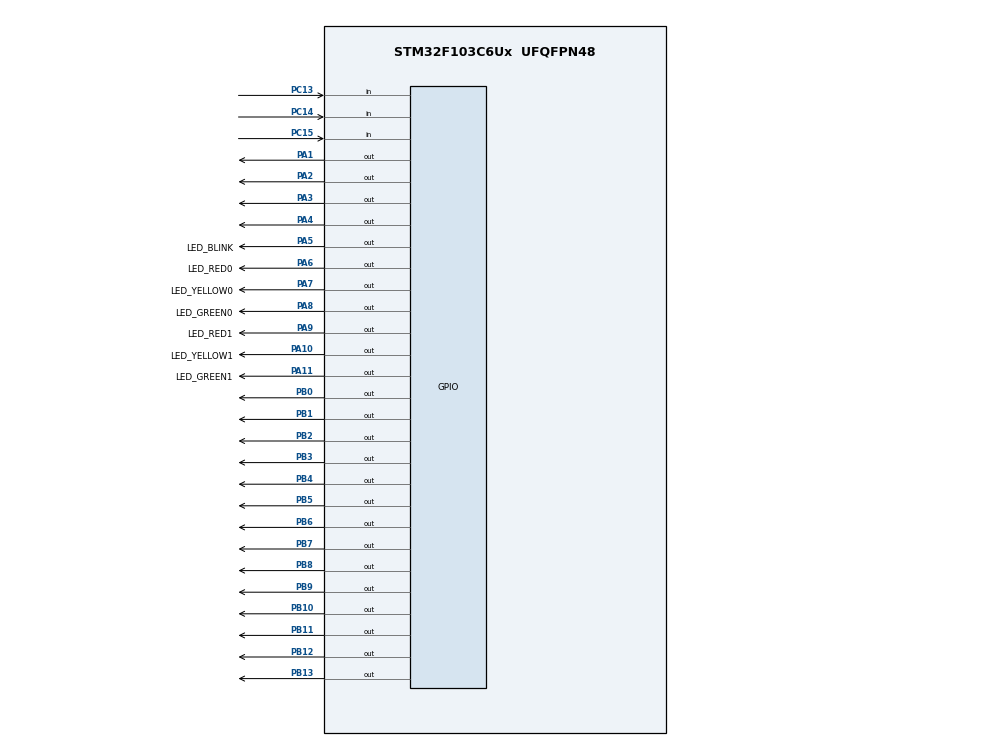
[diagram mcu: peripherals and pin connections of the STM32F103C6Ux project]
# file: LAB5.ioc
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Mcu.Family=STM32F1
Mcu.Name=STM32F103C6Ux
Mcu.Package=UFQFPN48
NVIC.PriorityGroup=NVIC_PRIORITYGROUP_4
NVIC.TIM2_IRQn=true\:0\:0\:false\:false\:true\:true\:true
PA1.Signal=GPIO_Output
PA10.GPIO_Label=LED_YELLOW1
PA10.Signal=GPIO_Output
PA11.GPIO_Label=LED_GREEN1
PA11.Signal=GPIO_Output
PA2.Signal=GPIO_Output
PA3.Signal=GPIO_Output
PA4.Signal=GPIO_Output
PA5.GPIO_Label=LED_BLINK
PA5.Signal=GPIO_Output
PA6.GPIO_Label=LED_RED0
PA6.Signal=GPIO_Output
PA7.GPIO_Label=LED_YELLOW0
PA7.Signal=GPIO_Output
PA8.GPIO_Label=LED_GREEN0
PA8.Signal=GPIO_Output
PA9.GPIO_Label=LED_RED1
PA9.Signal=GPIO_Output
PB0.Signal=GPIO_Output
PB1.Signal=GPIO_Output
PB10.Signal=GPIO_Output
PB11.Signal=GPIO_Output
PB12.Signal=GPIO_Output
PB13.Signal=GPIO_Output
PB2.Signal=GPIO_Output
PB3.Signal=GPIO_Output
PB4.Signal=GPIO_Output
PB5.Signal=GPIO_Output
PB6.Signal=GPIO_Output
PB7.Signal=GPIO_Output
PB8.Signal=GPIO_Output
PB9.Signal=GPIO_Output
PC13-TAMPER-RTC.GPIO_PuPd=GPIO_PULLUP
PC13-TAMPER-RTC.Signal=GPIO_Input
PC14-OSC32_IN.GPIO_PuPd=GPIO_PULLUP
PC14-OSC32_IN.Signal=GPIO_Input
PC15-OSC32_OUT.GPIO_PuPd=GPIO_PULLUP
PC15-OSC32_OUT.Signal=GPIO_Input
ProjectManager.HeapSize=0x200
ProjectManager.StackSize=0x400
ProjectManager.TargetToolchain=STM32CubeIDE
RCC.APB1Freq_Value=8000000
RCC.APB2Freq_Value=8000000
TIM2.Period=9
TIM2.Prescaler=7999
VP_SYS_VS_ND.Mode=No_Debug
VP_TIM2_VS_ClockSourceINT.Mode=Internal
board=custom

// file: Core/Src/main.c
/* USER CODE BEGIN Header */
/**
  ******************************************************************************
  * @file           : main.c
  * @brief          : Main program body
  ******************************************************************************
  * @attention
  *
  * <h2><center>&copy; Copyright (c) 2025 STMicroelectronics.
  * All rights reserved.</center></h2>
  *
  * This software component is licensed by ST under BSD 3-Clause license,
  * the "License"; You may not use this file except in compliance with the
  * License. You may obtain a copy of the License at:
  *                        opensource.org/licenses/BSD-3-Clause
  *
  ******************************************************************************
  */
/* USER CODE END Header */
#include "main.h"

/* USER CODE BEGIN Includes */
#include "scheduler.h"
/* USER CODE END Includes */

TIM_HandleTypeDef htim2;

/* USER CODE BEGIN PV */

void LED_monitor(int num){
	switch(num){
	case 0 :
		HAL_GPIO_WritePin(LED_RED0_GPIO_Port, LED_RED0_Pin, GPIO_PIN_SET);
		HAL_GPIO_WritePin(LED_GREEN0_GPIO_Port, LED_GREEN0_Pin, GPIO_PIN_RESET);
		HAL_GPIO_WritePin(LED_YELLOW0_GPIO_Port, LED_YELLOW0_Pin, GPIO_PIN_SET);
		break;
	case 1 :
		HAL_GPIO_WritePin(LED_RED0_GPIO_Port, LED_RED0_Pin, GPIO_PIN_SET);
		HAL_GPIO_WritePin(LED_GREEN0_GPIO_Port, LED_GREEN0_Pin, GPIO_PIN_SET);
		HAL_GPIO_WritePin(LED_YELLOW0_GPIO_Port, LED_YELLOW0_Pin, GPIO_PIN_RESET);
		break;
	case 2 :
		HAL_GPIO_WritePin(LED_RED0_GPIO_Port, LED_RED0_Pin, GPIO_PIN_RESET);
		HAL_GPIO_WritePin(LED_GREEN0_GPIO_Port, LED_GREEN0_Pin, GPIO_PIN_SET);
		HAL_GPIO_WritePin(LED_YELLOW0_GPIO_Port, LED_YELLOW0_Pin, GPIO_PIN_SET);
		break;
	default :
		HAL_GPIO_WritePin(LED_RED0_GPIO_Port, LED_RED0_Pin, GPIO_PIN_SET);
		HAL_GPIO_WritePin(LED_GREEN0_GPIO_Port, LED_GREEN0_Pin, GPIO_PIN_SET);
		HAL_GPIO_WritePin(LED_YELLOW0_GPIO_Port, LED_YELLOW0_Pin, GPIO_PIN_SET);
		break;
	}
}

uint8_t table[10] = {
    0b1000000, // 0
    0b1111001, // 1
    0b0100100, // 2
    0b0110000, // 3
    0b0011001, // 4
    0b0010010, // 5
    0b0000010, // 6
    0b1111000, // 7
    0b0000000, // 8
    0b0010000 // 9
};

void display7SEG(int num){
	uint8_t n= table[num];
	GPIOB->ODR= (GPIOB->ODR & 0xFFFFFF80)|n;
}

void task0(){
	HAL_GPIO_TogglePin(LED_RED_GPIO_Port, LED_RED_Pin);
}

int num=0;
void task1(){
	display7SEG(num);
	if(num<9) num++;
	else num=0;
}

int seq=0;
void task2(){
	LED_monitor(seq);
	if(seq<2) seq++;
	else seq=0;
}

void task3(){
	HAL_GPIO_TogglePin(LED_PINK_GPIO_Port, LED_PINK_Pin);
}
void task4(){
	HAL_GPIO_TogglePin(LED_BI_GPIO_Port, LED_BI_Pin);
}

/* USER CODE END PV */

void SystemClock_Config(void);
static void MX_TIM2_Init(void);
static void MX_GPIO_Init(void);

int main(void)
{

  /* MCU Configuration--------------------------------------------------------*/

  /* Reset of all peripherals, Initializes the Flash interface and the Systick. */
  HAL_Init();

  /* Configure the system clock */
  SystemClock_Config();

  /* Initialize all configured peripherals */
  MX_TIM2_Init();
  MX_GPIO_Init();
  /* USER CODE BEGIN 2 */
  HAL_TIM_Base_Start_IT(&htim2);
  /* USER CODE END 2 */

  /* Infinite loop */
  /* USER CODE BEGIN WHILE */
  SCH_Init();
  SCH_Add_Task(task0,0, 50);
  SCH_Add_Task(task1,0, 100);
  SCH_Add_Task(task2,0, 150);
  SCH_Add_Task(task3,0, 200);
  SCH_Add_Task(task4,250, 0);

  while (1)
  {
	  SCH_Dispatch_Tasks();
    /* USER CODE END WHILE */

  }
}

void SystemClock_Config(void)
{
  RCC_OscInitTypeDef RCC_OscInitStruct = {0};
  RCC_ClkInitTypeDef RCC_ClkInitStruct = {0};

  /** Initializes the RCC Oscillators according to the specified parameters
  * in the RCC_OscInitTypeDef structure.
  */
  RCC_OscInitStruct.OscillatorType = RCC_OSCILLATORTYPE_HSI;
  RCC_OscInitStruct.HSIState = RCC_HSI_ON;
  RCC_OscInitStruct.HSICalibrationValue = RCC_HSICALIBRATION_DEFAULT;
  RCC_OscInitStruct.PLL.PLLState = RCC_PLL_NONE;
  if (HAL_RCC_OscConfig(&RCC_OscInitStruct) != HAL_OK)
  {
    Error_Handler();
  }
  /** Initializes the CPU, AHB and APB buses clocks
  */
  RCC_ClkInitStruct.ClockType = RCC_CLOCKTYPE_HCLK|RCC_CLOCKTYPE_SYSCLK
                              |RCC_CLOCKTYPE_PCLK1|RCC_CLOCKTYPE_PCLK2;
  RCC_ClkInitStruct.SYSCLKSource = RCC_SYSCLKSOURCE_HSI;
  RCC_ClkInitStruct.AHBCLKDivider = RCC_SYSCLK_DIV1;
  RCC_ClkInitStruct.APB1CLKDivider = RCC_HCLK_DIV1;
  RCC_ClkInitStruct.APB2CLKDivider = RCC_HCLK_DIV1;

  if (HAL_RCC_ClockConfig(&RCC_ClkInitStruct, FLASH_LATENCY_0) != HAL_OK)
  {
    Error_Handler();
  }
}

static void MX_TIM2_Init(void)
{

  TIM_ClockConfigTypeDef sClockSourceConfig = {0};
  TIM_MasterConfigTypeDef sMasterConfig = {0};

  htim2.Instance = TIM2;
  htim2.Init.Prescaler = 7999;
  htim2.Init.CounterMode = TIM_COUNTERMODE_UP;
  htim2.Init.Period = 9;
  htim2.Init.ClockDivision = TIM_CLOCKDIVISION_DIV1;
  htim2.Init.AutoReloadPreload = TIM_AUTORELOAD_PRELOAD_DISABLE;
  if (HAL_TIM_Base_Init(&htim2) != HAL_OK)
  {
    Error_Handler();
  }
  sClockSourceConfig.ClockSource = TIM_CLOCKSOURCE_INTERNAL;
  if (HAL_TIM_ConfigClockSource(&htim2, &sClockSourceConfig) != HAL_OK)
  {
    Error_Handler();
  }
  sMasterConfig.MasterOutputTrigger = TIM_TRGO_RESET;
  sMasterConfig.MasterSlaveMode = TIM_MASTERSLAVEMODE_DISABLE;
  if (HAL_TIMEx_MasterConfigSynchronization(&htim2, &sMasterConfig) != HAL_OK)
  {
    Error_Handler();
  }

}

static void MX_GPIO_Init(void)
{
  GPIO_InitTypeDef GPIO_InitStruct = {0};

  /* GPIO Ports Clock Enable */
  __HAL_RCC_GPIOA_CLK_ENABLE();
  __HAL_RCC_GPIOB_CLK_ENABLE();

  /*Configure GPIO pin Output Level */
  HAL_GPIO_WritePin(GPIOA, LED_RED_Pin|LED_RED0_Pin|LED_YELLOW0_Pin|LED_GREEN0_Pin
                          |LED_PINK_Pin|LED_BI_Pin, GPIO_PIN_SET);

  /*Configure GPIO pin Output Level */
  HAL_GPIO_WritePin(GPIOB, GPIO_PIN_0|GPIO_PIN_1|GPIO_PIN_2|GPIO_PIN_3
                          |GPIO_PIN_4|GPIO_PIN_5|GPIO_PIN_6, GPIO_PIN_RESET);

  /*Configure GPIO pins : LED_RED_Pin LED_RED0_Pin LED_YELLOW0_Pin LED_GREEN0_Pin
                           LED_PINK_Pin LED_BI_Pin */
  GPIO_InitStruct.Pin = LED_RED_Pin|LED_RED0_Pin|LED_YELLOW0_Pin|LED_GREEN0_Pin
                          |LED_PINK_Pin|LED_BI_Pin;
  GPIO_InitStruct.Mode = GPIO_MODE_OUTPUT_PP;
  GPIO_InitStruct.Pull = GPIO_NOPULL;
  GPIO_InitStruct.Speed = GPIO_SPEED_FREQ_LOW;
  HAL_GPIO_Init(GPIOA, &GPIO_InitStruct);

  /*Configure GPIO pins : PB0 PB1 PB2 PB3
                           PB4 PB5 PB6 */
  GPIO_InitStruct.Pin = GPIO_PIN_0|GPIO_PIN_1|GPIO_PIN_2|GPIO_PIN_3
                          |GPIO_PIN_4|GPIO_PIN_5|GPIO_PIN_6;
  GPIO_InitStruct.Mode = GPIO_MODE_OUTPUT_PP;
  GPIO_InitStruct.Pull = GPIO_NOPULL;
  GPIO_InitStruct.Speed = GPIO_SPEED_FREQ_LOW;
  HAL_GPIO_Init(GPIOB, &GPIO_InitStruct);

}

/* USER CODE BEGIN 4 */
void HAL_TIM_PeriodElapsedCallback(TIM_HandleTypeDef *htim){
	SCH_Update();
}
/* USER CODE END 4 */

void Error_Handler(void)
{
  __disable_irq();
  while (1)
  {
  }
}

/************************ (C) COPYRIGHT STMicroelectronics *****END OF FILE****/
